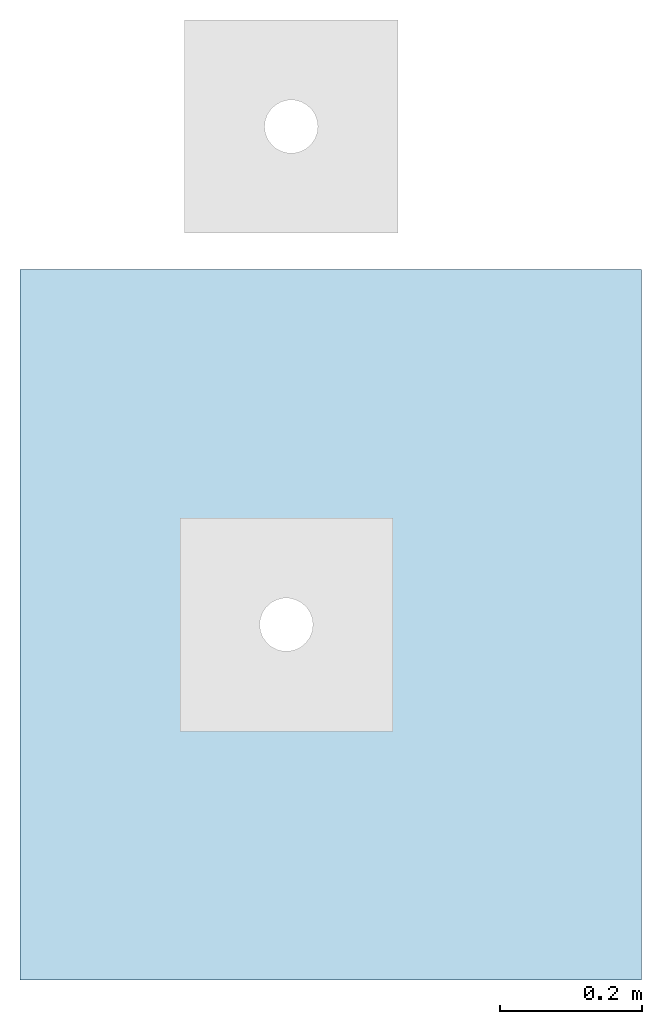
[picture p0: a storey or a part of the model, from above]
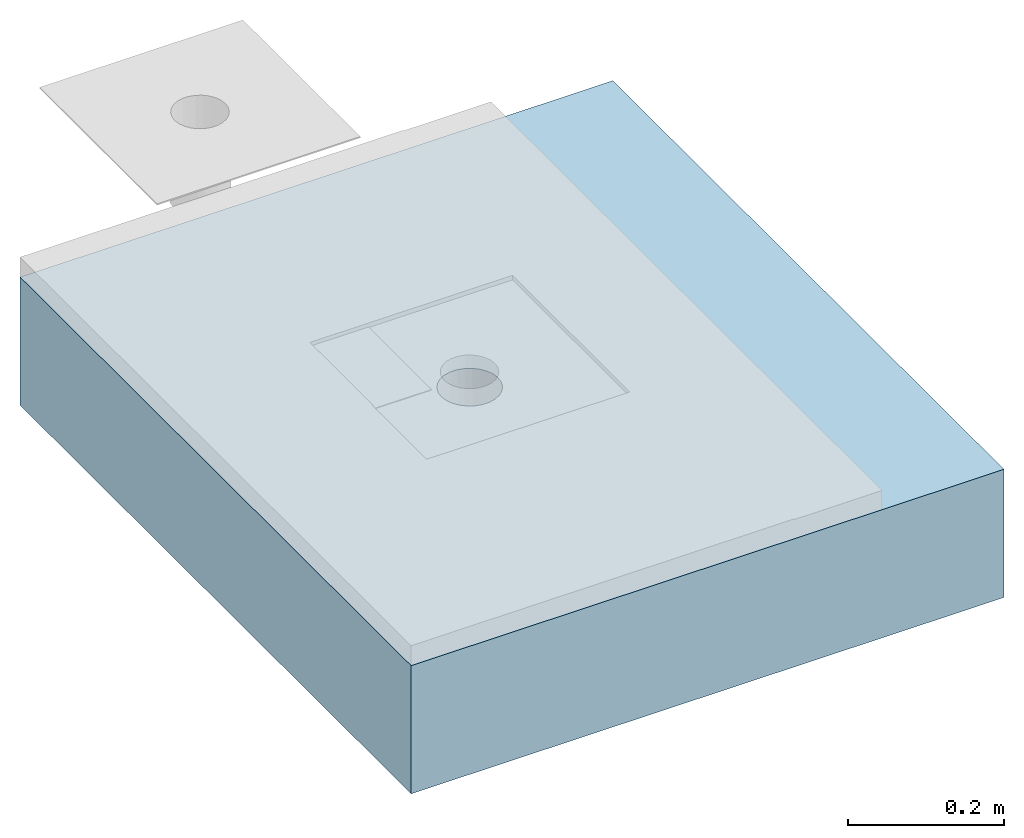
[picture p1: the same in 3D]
Properties of the parts of a building model (IFC2X3)

# File
Description: ViewDefinition [CoordinationView_V2.0], RevitIdentifiers [VersionGUID: e56f502e-c55e-4302-922e-01d117b02319, NumberOfSaves: 24], CoordinateReference [CoordinateBase: Coordenadas compartilhadas]
File name: 0001
Time: 2026-02-13T11:07:24
Written by: ODA IFC SDK 22.8
Made in: 22.1.50.17 - Exporter 22.6.2.0 - IU alternativa 22.6.2.0

# IfcProject, 0001
LongName: Tratamento de Ralo - VIABOC RALO 75mm; Phase: Status do projeto

# IfcSite, Default
RefLatitude: 42, 21, 31, 181944; RefLongitude: -71, -3, -24, -263304; RefElevation: 0 m

# IfcBuilding
Pset_BuildingCommon - NumberOfStoreys: 1; IsLandmarked: no

# IfcBuildingStorey: Nível:Cabeça de 8 mm, ARQ Térreo
LongName: ARQ Térreo; Elevation: -0.0025238 m

# IfcBuildingElementProxy: IMPER:IMPER:433934, IMPER:IMPER:433934:IMPER:433934 : IMPER:IMPER:433934:291594
In: ARQ Térreo
Type - Material: #Impermeabilização, Plástico, #argamassa
Type - Pset_BuildingElementProxyCommon - Reference: IMPER
Type - Pset_QuantityTakeOff - Reference: IMPER
Type - Pset_ProvisionForVoid - Width: 0.952886 m; Height: 0.00103887 m; Depth: 2.6 m
Pset_BuildingElementProxyCommon - sets with these values: 2

# IfcBuildingElementProxy: Modelos genéricos 1:Modelos genéricos 1, Modelos genéricos 1:Modelos genéricos 1:311338
In: ARQ Térreo
Type - Material: _Viaboc
Pset_BuildingElementProxyCommon - Reference: Modelos genéricos 1; sets with these values: 2
Pset_ProvisionForVoid - Width: 0.3 m; Height: 0.3 m; Depth: 0.3 m

# IfcBuildingElementProxy: Viaboc Ralo 75mm:Viaboc Ralo 75mm, Viaboc Ralo 75mm:Viaboc Ralo 75mm:316010
In: ARQ Térreo
Type - Material: _Viaboc
Pset_BuildingElementProxyCommon - Reference: Viaboc Ralo 75mm; sets with these values: 2
Pset_ProvisionForVoid - Width: 0.3 m; Height: 0.3 m; Depth: 0.3 m

# IfcOpeningElement: Opening, Piso:Piso:LAJE CONCRETO:293941
In: ARQ Térreo
Pset_OpeningElementCommon - Reference: Piso:LAJE CONCRETO; sets with these values: 2

# IfcSlab: Piso:Piso:LAJE CONCRETO, Piso:Piso:LAJE CONCRETO:293944
In: ARQ Térreo
Type - PredefinedType: FLOOR; Material: #concreto 0.2 m
Type - Pset_SlabCommon - IsExternal: no
Pset_QuantityTakeOff - Reference: Piso:LAJE CONCRETO; sets with these values: 2
Pset_SlabCommon - Reference: Piso:LAJE CONCRETO; LoadBearing: no; PitchAngle: 0 deg
